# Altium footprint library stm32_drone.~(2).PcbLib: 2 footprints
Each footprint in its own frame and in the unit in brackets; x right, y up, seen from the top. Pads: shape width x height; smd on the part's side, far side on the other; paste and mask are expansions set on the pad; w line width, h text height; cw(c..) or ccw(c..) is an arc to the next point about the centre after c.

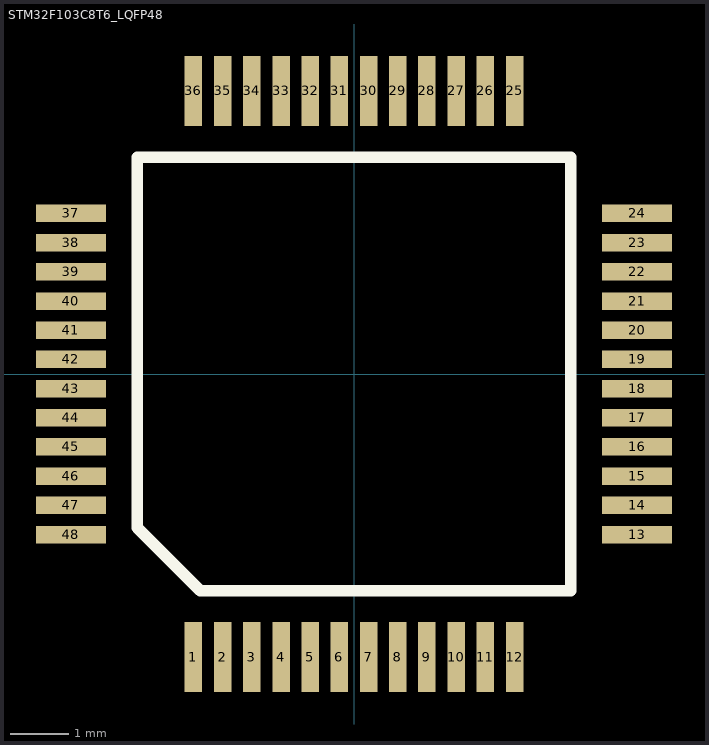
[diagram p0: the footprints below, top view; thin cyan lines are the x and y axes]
## PCBComponent_1 [mm]

## STM32F103C8T6_LQFP48 [mm]
pads (48):
  rect 0.3x1.2 smd mask+0.05: 1(-2.75,-4.85) 2(-2.25,-4.85) 3(-1.75,-4.85) 4(-1.25,-4.85) 5(-0.75,-4.85) 6(-0.25,-4.85) 7(0.25,-4.85) 8(0.75,-4.85) 9(1.25,-4.85) 10(1.75,-4.85) 11(2.25,-4.85) 12(2.75,-4.85) 25(2.75,4.85) 26(2.25,4.85) 27(1.75,4.85) 28(1.25,4.85) 29(0.75,4.85) 30(0.25,4.85) 31(-0.25,4.85) 32(-0.75,4.85) 33(-1.25,4.85) 34(-1.75,4.85) 35(-2.25,4.85) 36(-2.75,4.85)
  rect 1.2x0.3 smd mask+0.05: 13(4.85,-2.75) 14(4.85,-2.25) 15(4.85,-1.75) 16(4.85,-1.25) 17(4.85,-0.75) 18(4.85,-0.25) 19(4.85,0.25) 20(4.85,0.75) 21(4.85,1.25) 22(4.85,1.75) 23(4.85,2.25) 24(4.85,2.75) 37(-4.85,2.75) 38(-4.85,2.25) 39(-4.85,1.75) 40(-4.85,1.25) 41(-4.85,0.75) 42(-4.85,0.25) 43(-4.85,-0.25) 44(-4.85,-0.75) 45(-4.85,-1.25) 46(-4.85,-1.75) 47(-4.85,-2.25) 48(-4.85,-2.75)
Top Overlay:
  lines w0.2: -3.715,-2.635 -3.715,3.715 3.715,3.715 3.715,-3.715 -2.635,-3.715 -3.715,-2.635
